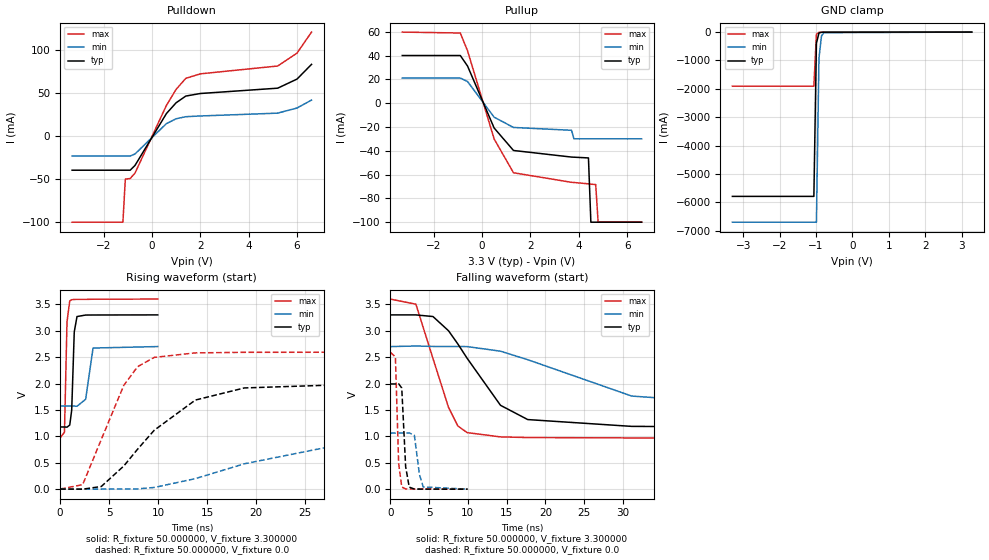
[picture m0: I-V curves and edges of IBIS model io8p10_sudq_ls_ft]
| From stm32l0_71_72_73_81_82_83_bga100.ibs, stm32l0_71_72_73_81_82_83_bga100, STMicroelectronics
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|   Model io8p10_sudq_ls_ft
[Model]  io8p10_sudq_ls_ft
Model_type I/O
Polarity   Non-Inverting
Enable   Active-Low
Vinl =   0.990000V
Vinh =   2.310000V
Vmeas =  1.650000V
Cref =   50.000000pF
Rref =   100.000000M
Vref =   0.0V
C_comp   2.343000pF   2.309800pF   2.393900pF
[Temperature Range]   25.000000   0.125000k   -40.000000
[Pullup Reference]   3.300000V   2.700000V   3.600000V
[Pulldown Reference]   0.0V   0.0V   0.0V
[POWER Clamp Reference]   3.300000V   2.700000V   3.600000V
[GND Clamp Reference]   0.0V   0.0V   0.0V
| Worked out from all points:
|   slope of the pulldown table from 0 to 0.495 V, typ, clamps not added: 22.6 ohm
|   slope of the pullup table from 0 to 0.495 V, typ, clamps not added: 23.9 ohm
|   GND clamp passes 1 mA (typ) near -0.64 V on its own axis
|   rising waveform, R_fixture 50.000000, V_fixture 3.300000: 20-80 % time 207ps typ, 360ps min, 164ps max; typ from 1.18 V to 3.3 V
|   rising waveform, R_fixture 50.000000, V_fixture 0.0: 20-80 % time 6.56ns typ, 13.7ns min, 3.47ns max; typ from 0 V to 1.99 V
|   falling waveform, R_fixture 50.000000, V_fixture 3.300000: 20-80 % time 6ns typ, 12.7ns min, 3.3ns max; typ from 3.3 V to 1.18 V
|   falling waveform, R_fixture 50.000000, V_fixture 0.0: 20-80 % time 380ps typ, 554ps min, 301ps max; typ from 1.99 V to 0 V
[Pulldown]
|Voltage   I(typ)   I(min)   I(max)
-3.3V     -39.8mA    -23.37mA   -100mA
-1.2V     -39.8mA    -23.37mA   -100mA
-1.1V     -39.8mA    -23.37mA   -50.1mA
-900mV    -39.8mA    -23.37mA   -49.43mA
-700mV    -34.25mA   -21mA      -43.13mA
600mV     25.84mA    14.18mA    35.34mA
1V        38.32mA    19.82mA    53.81mA
1.4V      46.09mA    22.19mA    66.63mA
2V        49.05mA    23.02mA    71.83mA
5.2V      55.23mA    26.32mA    80.92mA
6V        65.76mA    32.26mA    95.84mA
6.6V      82.81mA    41.43mA    120.2mA
[Pullup]
|Voltage   I(typ)   I(min)   I(max)
-3.3V     40.03mA    21.09mA    59.71mA
-900mV    40.03mA    21.09mA    58.93mA
-600mV    31.19mA    18.17mA    44.03mA
500mV     -20.88mA   -11.78mA   -30.07mA
1.3V      -39.75mA   -20.41mA   -58.47mA
3.7V      -45.29mA   -22.8mA    -66.5mA
3.8V      -45.39mA   -30mA      -66.64mA
4.4V      -46mA      -30mA      -67.77mA
4.5V      -100mA     -30mA      -68.06mA
4.7V      -100mA     -30mA      -68.4mA
4.8V      -100mA     -30mA      -100mA
6.6V      -100mA     -30mA      -100mA
[GND_clamp]
|Voltage   I(typ)   I(min)   I(max)
-3.3V     -5.787A    -6.696A    -1.906A
-1.06V    -5.787A    -6.696A    -1.906A
-990mV    -393.4mA   -6.696A    -70.75mA
-920mV    -33.02mA   -919.4mA   -10.9mA
-850mV    -6.829mA   -131.3mA   -6.521mA
-780mV    -3.478mA   -21.06mA   -4.208mA
3.28V     0A         0A         0A
[POWER_clamp]
|Voltage   I(typ)   I(min)   I(max)
-3.28V    0A         0A         0A
0V        0A         0A         0A
[Ramp]
| variable   typ   min   max
dV/dt_r  1.19496/6.55113n   0.62916/13.60877n   1.55568/3.47100n
dV/dt_f  1.27356/5.99568n   0.65286/12.57445n   1.57788/3.29118n
R_load = 50.000000
[Rising Waveform]
R_fixture= 50.000000
V_fixture= 3.300000
V_fixture_min= 2.700000
V_fixture_max= 3.600000
|time   V(typ)   V(min)   V(max)
0s        1.177V     1.573V     970.2mV
440.4ps   1.176V     1.573V     1.077V
700.7ps   1.173V     1.573V     3.169V
981ps     1.213V     1.573V     3.566V
1.181ns   1.497V     1.573V     3.588V
1.441ns   2.978V     1.572V     3.593V
1.722ns   3.269V     1.569V     3.594V
2.603ns   3.297V     1.701V     3.594V
3.363ns   3.298V     2.672V     3.597V
9.97ns    3.3V       2.7V       3.6V
[Rising Waveform]
R_fixture= 50.000000
V_fixture= 0.0
V_fixture_min= 0.0
V_fixture_max= 0.0
|time   V(typ)   V(min)   V(max)
0s        -119.7nV   -5.789uV   368.3uV
2.302ns   -2.093mV   -1.676mV   83.36mV
4.204ns   48.68mV    -891.8uV   940.8mV
6.507ns   437.9mV    -540.9uV   1.967V
7.908ns   754.6mV    3.219mV    2.318V
9.61ns    1.114V     30.19mV    2.495V
13.81ns   1.686V     197.4mV    2.58V
18.82ns   1.916V     478.6mV    2.591V
30.73ns   1.988V     919.8mV    2.593V
49.85ns   1.992V     1.062V     2.593V
[Falling Waveform]
R_fixture= 50.000000
V_fixture= 3.300000
V_fixture_min= 2.700000
V_fixture_max= 3.600000
|time   V(typ)   V(min)   V(max)
0s        3.3V       2.7V       3.6V
3.303ns   3.3V       2.711V     3.503V
5.506ns   3.269V     2.703V     2.474V
7.508ns   3V         2.702V     1.549V
8.709ns   2.75V      2.701V     1.197V
9.91ns    2.478V     2.7V       1.071V
14.21ns   1.588V     2.613V     989.8mV
17.72ns   1.318V     2.452V     977.4mV
31.13ns   1.189V     1.763V     970.4mV
49.85ns   1.177V     1.573V     970.2mV
[Falling Waveform]
R_fixture= 50.000000
V_fixture= 0.0
V_fixture_min= 0.0
V_fixture_max= 0.0
|time   V(typ)   V(min)   V(max)
0s        1.992V     1.062V     2.593V
660.7ps   1.992V     1.062V     2.504V
1.081ns   1.996V     1.062V     484.6mV
1.481ns   1.914V     1.062V     41.19mV
1.982ns   425.6mV    1.061V     4.837mV
2.442ns   38.62mV    1.065V     3.215mV
3.103ns   2.452mV    1.023V     2.985mV
3.764ns   1.24mV     276.5mV    2.941mV
4.244ns   1.077mV    42.35mV    2.466mV
9.97ns    -119.7nV   -5.789uV   368.3uV
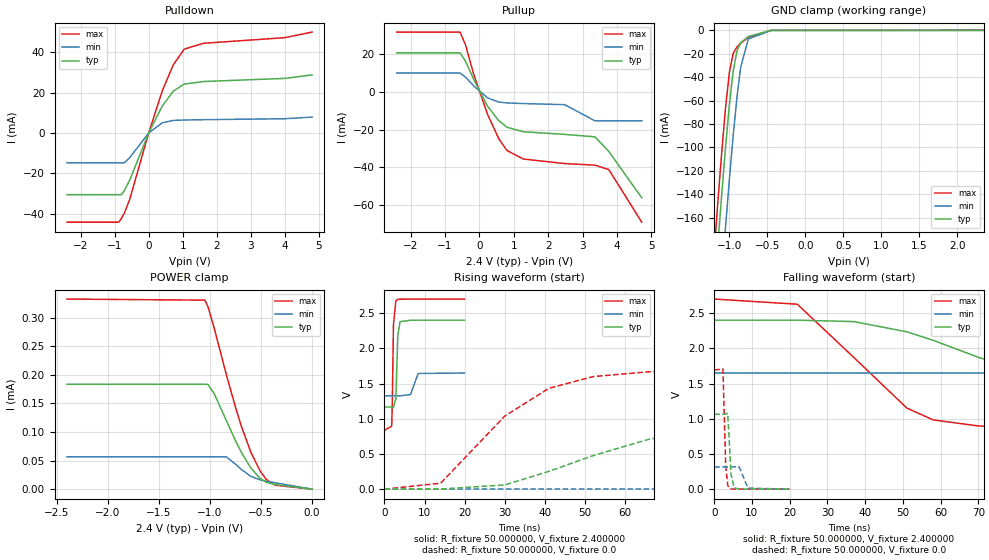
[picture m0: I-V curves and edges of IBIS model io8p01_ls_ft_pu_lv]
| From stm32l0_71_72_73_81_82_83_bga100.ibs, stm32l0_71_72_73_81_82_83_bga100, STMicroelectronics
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|   Model io8p01_ls_ft_pu_lv
[Model]  io8p01_ls_ft_pu_lv
Model_type I/O
Polarity   Non-Inverting
Enable   Active-Low
Vinl =   0.720000V
Vinh =   1.680000V
Vmeas =  1.200000V
Cref =   50.000000pF
Rref =   100.000000M
Vref =   0.0V
C_comp   4.521100pF   4.438000pF   4.578000pF
[Temperature Range]   25.000000   0.105000k   -40.000000
[Pullup Reference]   2.400000V   1.650000V   2.700000V
[Pulldown Reference]   0.0V   0.0V   0.0V
[POWER Clamp Reference]   2.400000V   1.650000V   2.700000V
[GND Clamp Reference]   0.0V   0.0V   0.0V
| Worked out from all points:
|   slope of the pulldown table from 0 to 0.36 V, typ, clamps not added: 29.5 ohm
|   slope of the pullup table from 0 to 0.36 V, typ, clamps not added: 33.2 ohm
|   GND clamp passes 1 mA (typ) near -0.59 V on its own axis
|   rising waveform, R_fixture 50.000000, V_fixture 2.400000: 20-80 % time 359ps typ, 683ps min, 299ps max; typ from 1.17 V to 2.4 V
|   rising waveform, R_fixture 50.000000, V_fixture 0.0: 20-80 % time 39.4ns typ, 107ns min, 19.3ns max; typ from 0.001 V to 1.06 V
|   falling waveform, R_fixture 50.000000, V_fixture 2.400000: 20-80 % time 41.1ns typ, 105ns min, 20.5ns max; typ from 2.4 V to 1.17 V
|   falling waveform, R_fixture 50.000000, V_fixture 0.0: 20-80 % time 620ps typ, 979ps min, 517ps max; typ from 1.06 V to 0.001 V
[Pulldown]
|Voltage   I(typ)   I(min)   I(max)
-2.4V     -30.64mA   -14.84mA   -44.29mA
-880mV    -30.64mA   -14.84mA   -44.29mA
-800mV    -30.64mA   -14.84mA   -42.37mA
-720mV    -28.74mA   -14.84mA   -39.91mA
-560mV    -23.52mA   -12.34mA   -33.09mA
0V        -765nA     -61nA      -2.526uA
400mV     13.38mA    4.998mA    20.91mA
720mV     20.62mA    6.178mA    33.69mA
1.04V     24.19mA    6.384mA    41.49mA
1.6V      25.46mA    6.544mA    44.42mA
4V        27.03mA    7.028mA    47.23mA
4.8V      28.76mA    7.817mA    49.99mA
[Pullup]
|Voltage   I(typ)   I(min)   I(max)
-2.4V     20.55mA    9.938mA    31.51mA
-560mV    20.55mA    9.938mA    31.51mA
-400mV    16.07mA    7.669mA    24.65mA
-160mV    6.379mA    3.022mA    8.973mA
240mV     -7.653mA   -3.251mA   -12mA
560mV     -15.22mA   -5.43mA    -24.63mA
800mV     -18.73mA   -5.908mA   -31mA
1.28V     -21.13mA   -6.236mA   -35.54mA
2.48V     -22.51mA   -6.818mA   -37.93mA
3.36V     -23.83mA   -15.36mA   -38.77mA
3.76V     -31.49mA   -15.36mA   -41.07mA
4.72V     -56mA      -15.36mA   -68.89mA
[GND_clamp]
|Voltage   I(typ)   I(min)   I(max)
-2.4V     -1.379A    -1.445A    -1.35A
-1.2V     -225.9mA   -297.5mA   -189.2mA
-1.15V    -182mA     -253.1mA   -145.3mA
-1.1V     -139.6mA   -209.7mA   -103.5mA
-1.05V    -99.61mA   -167.6mA   -65.7mA
-1V       -63.67mA   -127.3mA   -35.89mA
-950mV    -35mA      -89.93mA   -19.87mA
-900mV    -17.67mA   -57.01mA   -14.12mA
-850mV    -10.49mA   -31.18mA   -11mA
-750mV    -5.288mA   -7.322mA   -5.997mA
-450mV    -33.57uA   -87.56uA   -14.35uA
2.35V     0A         0A         0A
[POWER_clamp]
|Voltage   I(typ)   I(min)   I(max)
-2.4V     183.5uA    56.67uA    332.6uA
-1.05V    183.5uA    56.67uA    330.7uA
-1.02V    183.2uA    56.67uA    319.4uA
-960mV    167.5uA    56.67uA    282.5uA
-840mV    120.2uA    56.67uA    200.6uA
-750mV    84.84uA    43.79uA    143.2uA
-690mV    63.63uA    34.11uA    108.8uA
-600mV    37.11uA    22.45uA    64.86uA
-510mV    18.78uA    16.35uA    32.08uA
-450mV    12.09uA    14.02uA    17.37uA
-360mV    8.168uA    11.12uA    6.844uA
0V        0A         0A         0A
[Ramp]
| variable   typ   min   max
dV/dt_r  0.63803/39.36359n   0.18802/0.10676u   1.01576/19.32218n
dV/dt_f  0.73962/41.03145n   0.19194/0.10481u   1.11752/20.44767n
R_load = 50.000000
[Rising Waveform]
R_fixture= 50.000000
V_fixture= 2.400000
V_fixture_min= 1.650000
V_fixture_max= 2.700000
|time   V(typ)   V(min)   V(max)
0s        1.167V     1.327V     837.1mV
1.802ns   1.167V     1.327V     895.6mV
1.922ns   1.165V     1.327V     1.145V
2.242ns   1.161V     1.327V     2.339V
2.843ns   1.287V     1.327V     2.677V
3.323ns   2.184V     1.327V     2.696V
3.884ns   2.379V     1.326V     2.698V
6.486ns   2.399V     1.343V     2.699V
8.408ns   2.4V       1.643V     2.7V
19.94ns   2.4V       1.65V      2.7V
[Rising Waveform]
R_fixture= 50.000000
V_fixture= 0.0
V_fixture_min= 0.0
V_fixture_max= 0.0
|time   V(typ)   V(min)   V(max)
0s        917.2uV    1.344mV    570.3uV
14.01ns   2.459mV    2.471mV    85.1mV
30.03ns   60.8mV     2.471mV    1.039V
41.04ns   253.5mV    2.473mV    1.433V
52.05ns   476.7mV    2.483mV    1.599V
66.07ns   710.5mV    2.562mV    1.668V
90.09ns   936.1mV    4.31mV     1.691V
128.1ns   1.043V     51.42mV    1.694V
254.3ns   1.064V     265.9mV    1.694V
498.5ns   1.064V     315mV      1.694V
[Falling Waveform]
R_fixture= 50.000000
V_fixture= 2.400000
V_fixture_min= 1.650000
V_fixture_max= 2.700000
|time   V(typ)   V(min)   V(max)
0s        2.4V       1.65V      2.7V
22.02ns   2.4V       1.65V      2.627V
37.04ns   2.38V      1.65V      1.869V
51.05ns   2.235V     1.65V      1.152V
58.06ns   2.114V     1.65V      983.4mV
70.07ns   1.872V     1.65V      898.3mV
98.1ns    1.403V     1.65V      850.6mV
137.1ns   1.229V     1.637V     838.9mV
283.3ns   1.168V     1.39V      837mV
498.5ns   1.167V     1.327V     837.1mV
[Falling Waveform]
R_fixture= 50.000000
V_fixture= 0.0
V_fixture_min= 0.0
V_fixture_max= 0.0
|time   V(typ)   V(min)   V(max)
0s        1.064V     315mV      1.694V
2.322ns   1.064V     315mV      1.706V
3.043ns   1.066V     315mV      343.1mV
3.564ns   1.078V     315mV      63.07mV
3.844ns   838.4mV    314.9mV    25.88mV
4.444ns   219mV      314.6mV    4.713mV
5.285ns   19.73mV    317.5mV    1.267mV
6.607ns   1.375mV    319.2mV    988.4uV
8.929ns   1.003mV    15.4mV     785.5uV
19.94ns   917.2uV    1.344mV    570.3uV
